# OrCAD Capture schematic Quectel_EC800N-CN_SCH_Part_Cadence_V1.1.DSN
size A2

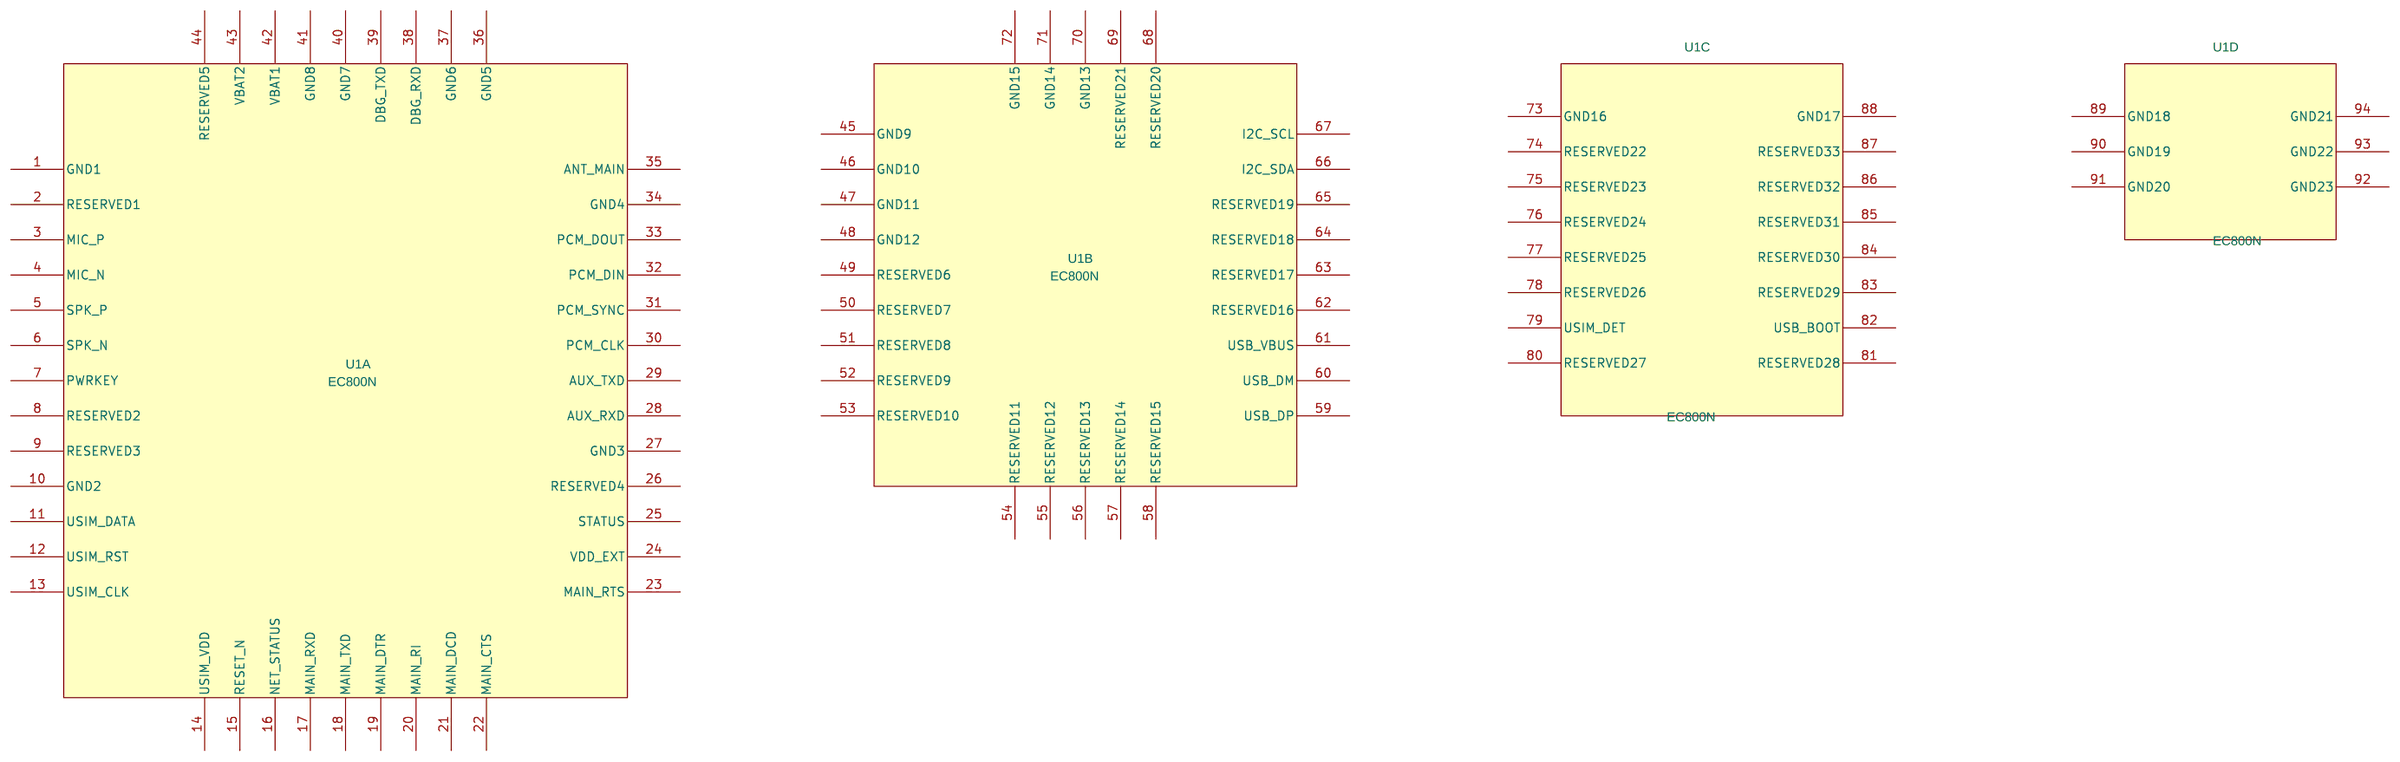
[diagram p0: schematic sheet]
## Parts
U1  EC800N  [EC800N]  (sections A,B,C,D)

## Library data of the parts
U1 = EC800N

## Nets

Not connected (* = marked no-connect by the designer): U1 1(GND1) 2(RESERVED1) 3(MIC_P) 4(MIC_N) 5(SPK_P) 6(SPK_N) 7(PWRKEY) 8(RESERVED2) 9(RESERVED3) 10(GND2) 11(USIM_DATA) 12(USIM_RST) 13(USIM_CLK) 14(USIM_VDD) 15(RESET_N) 16(NET_STATUS) 17(MAIN_RXD) 18(MAIN_TXD) 19(MAIN_DTR) 20(MAIN_RI) 21(MAIN_DCD) 22(MAIN_CTS) 23(MAIN_RTS) 24(VDD_EXT) 25(STATUS) 26(RESERVED4) 27(GND3) 28(AUX_RXD) 29(AUX_TXD) 30(PCM_CLK) 31(PCM_SYNC) 32(PCM_DIN) 33(PCM_DOUT) 34(GND4) 35(ANT_MAIN) 36(GND5) 37(GND6) 38(DBG_RXD) 39(DBG_TXD) 40(GND7) 41(GND8) 42(VBAT1) 43(VBAT2) 44(RESERVED5) 45(GND9) 46(GND10) 47(GND11) 48(GND12) 49(RESERVED6) 50(RESERVED7) 51(RESERVED8) 52(RESERVED9) 53(RESERVED10) 54(RESERVED11) 55(RESERVED12) 56(RESERVED13) 57(RESERVED14) 58(RESERVED15) 59(USB_DP) 60(USB_DM) 61(USB_VBUS) 62(RESERVED16) 63(RESERVED17) 64(RESERVED18) 65(RESERVED19) 66(I2C_SDA) 67(I2C_SCL) 68(RESERVED20) 69(RESERVED21) 70(GND13) 71(GND14) 72(GND15) 73(GND16) 74(RESERVED22) 75(RESERVED23) 76(RESERVED24) 77(RESERVED25) 78(RESERVED26) 79(USIM_DET) 80(RESERVED27) 81(RESERVED28) 82(USB_BOOT) 83(RESERVED29) 84(RESERVED30) 85(RESERVED31) 86(RESERVED32) 87(RESERVED33) 88(GND17) 89(GND18) 90(GND19) 91(GND20) 92(GND23) 93(GND22) 94(GND21)
